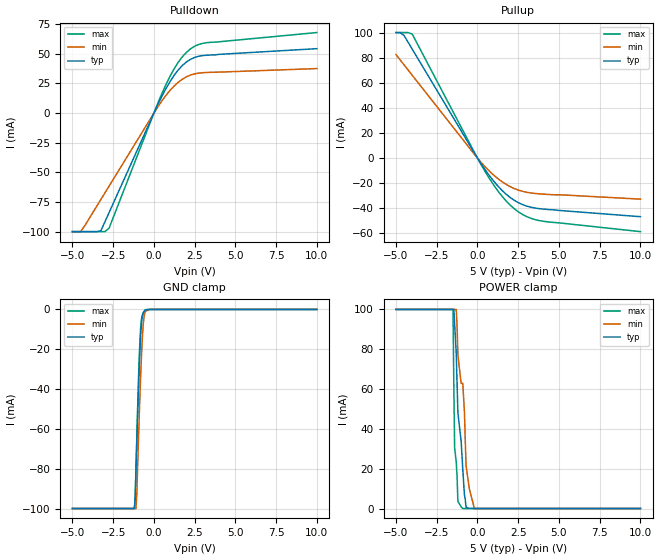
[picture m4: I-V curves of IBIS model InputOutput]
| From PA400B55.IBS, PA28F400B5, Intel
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|********************Input Output Model**************************
[Model]   InputOutput
Model_type   I/O
|   Model for DQ[15:0] pins.
Vinl = 0.8V
Vinh = 2.0V
|Variable   Typ   Min   Max
C_comp   8.91p   NA   10.5p
[Voltage Range]   5.0V   4.5V   5.5V
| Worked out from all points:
|   slope of the pulldown table from 0 to 0.75 V, typ, clamps not added: 35.7 ohm
|   slope of the pullup table from 0 to 0.75 V, typ, clamps not added: 52.4 ohm
|   GND clamp passes 1 mA (typ) near -0.59 V on its own axis
|   POWER clamp passes 1 mA (typ) near -0.70 V on its own axis
[Pulldown]
| [Pullup] and [Pulldown] IV curves include only the current through
| the channels of output driver transistors when outputs are enabled
| with OE# = VIL.  Although the output driver transistors have np and
| pn diodes inherently created by CMOS IC fabrication between the
| drain and bulk of n-channel and p-channel CMOS transistors,
| the current through these junction diodes is not included in
| [Pullup] or [Pulldown].  Instead that drain/bulk diode current is
| included in the [POWER_clamp] or [GND_clamp] sections, which are
| not dependent on the state of OE# or output data value.
|Voltage   I(typ)   I(min)   I(max)
-5V       -100mA     -100mA     -100mA
-4.5V     -100mA     -100mA     -100mA
-3.25V    -99.21mA   -72.83mA   -100mA
-3V       -91.58mA   -67.23mA   -100mA
-2.75V    -83.96mA   -61.63mA   -97.09mA
0V        0A         0A         0A
750mV     20.99mA    15.18mA    24.41mA
1.5V      36.53mA    26.1mA     43.01mA
2.25V     45.41mA    32.15mA    54.26mA
2.75V     47.97mA    33.77mA    57.93mA
3.25V     48.88mA    34.32mA    59.45mA
10V       54.4mA     37.6mA     68mA
[GND_clamp]
| [POWER_clamp] and [GND_clamp] IV curves describe ESD protection
| circuits PLUS some np and pn diodes which exist between the
| drain and bulk of n-channel and p-channel CMOS transistors.
| These drain/bulk diodes are inherent in CMOS IC fabrication,
| and are visible on the node of the I/O pin at all times.
| Even the drain/bulk diodes of output driver [Pullup] and [Powerdown]
| transistors are included in [POWER_clamp] or [GND_clamp], because
| these diodes contribute to I/O pin current even when the
| chip outputs are tristated by OE# = VIH.
| For example, when V forced on the I/O pin is large, we are
| forward biasing the pn diode at the drain/bulk interface in the
| p-channel pullup transistor.  Similarly, when V forced on the
| I/O pin is sufficiently negative with respect to the substrate
| ground, we are forward biasing the np diode at the drain/bulk
| interface in the n-channel pulldown transistor.  The effects
| of these diodes are included in [POWER_clamp] or [GND_clamp].
|Voltage   I(typ)   I(min)   I(max)
-5V       -100mA     -100mA     -100mA
-1.2V     -100mA     -100mA     -100mA
-1.15V    -94.55mA   -100mA     -96.67mA
-1.1V     -80.56mA   -100mA     -80.77mA
-1.05V    -66.88mA   -93.22mA   -65.22mA
-950mV    -41mA      -66.42mA   -36.42mA
-850mV    -19.48mA   -42.04mA   -14.41mA
-800mV    -11.39mA   -30.88mA   -7.73mA
-700mV    -3.273mA   -13.05mA   -2.625mA
-650mV    -1.9mA     -7.193mA   -1.603mA
-550mV    -562uA     -1.692mA   -398uA
10V       0A         0A         0A
[Pullup]
| (Voltages for [Pullup] and [POWER_clamp] are specified with
| negative respect to Vcc.  Reference the IBIS documentation
| for more information regarding Vtable = Vcc - Voutput.
| This method keeps -Vds constant for the values in all three
| columns across a line of the table.
| [Pullup] and [Pulldown] IV curves include only the current through
| the channels of output driver transistors when outputs are enabled
| with OE# = VIL.  Although the output driver transistors have np and
| pn diodes inherently created by CMOS IC fabrication between the
| drain and bulk of n-channel and p-channel CMOS transistors,
| the current through these junction diodes is not included in
| [Pullup] or [Pulldown].  Instead that drain/bulk diode current is
| included in the [POWER_clamp] or [GND_clamp] sections, which are
| not dependent on the state of OE# or output data value.
|Voltage  I(typ)   I(min)   I(max)
-5V       100mA      82.46mA    100mA
-4.75V    100mA      78.34mA    100mA
-4.5V     97.62mA    74.21mA    100mA
-4V       86.77mA    65.96mA    98.73mA
250mV     -5.046mA   -3.838mA   -5.815mA
750mV     -14.3mA    -10.62mA   -16.61mA
1.25V     -22.21mA   -16.32mA   -26.12mA
1.75V     -28.68mA   -20.87mA   -34.03mA
2.25V     -33.58mA   -24.23mA   -40.27mA
3V        -38.16mA   -27.19mA   -46.5mA
3.75V     -40.21mA   -28.43mA   -49.67mA
10V       -46.7mA    -32.7mA    -58.6mA
[POWER_clamp]
| (Voltages for [Pullup] and [POWER_clamp] are specified with
| negative respect to Vcc.  Reference the IBIS documentation
| for more information regarding Vtable = Vcc - Voutput.
| This method keeps -Vds constant for the values in all three
| columns across a line of the table.
| [POWER_clamp] and [GND_clamp] IV curves describe ESD protection
| circuits PLUS some np and pn diodes which exist between the
| drain and bulk of n-channel and p-channel CMOS transistors.
| These drain/bulk diodes are inherent in CMOS IC fabrication,
| and are visible on the node of the I/O pin at all times.
| Even the drain/bulk diodes of output driver [Pullup] and [Powerdown]
| transistors are included in [POWER_clamp] or [GND_clamp], because
| these diodes contribute to I/O pin current even when the
| chip outputs are tristated by OE# = VIH.
| For example, when V forced on the I/O pin is large, we are
| forward biasing the pn diode at the drain/bulk interface in the
| p-channel pullup transistor.  Similarly, when V forced on the
| I/O pin is sufficiently negative with respect to the substrate
| ground, we are forward biasing the np diode at the drain/bulk
| interface in the n-channel pulldown transistor.  The effects
| of these diodes are included in [POWER_clamp] or [GND_clamp].
|Voltage I(typ)   I(min)   I(max)
-5V       100mA      100mA      100mA
-1.5V     100mA      100mA      100mA
-1.45V    100mA      100mA      62.38mA
-1.4V     92.69mA    100mA      30.52mA
-1.3V     77.7mA     100mA      23.25mA
-1.2V     48.13mA    77.11mA    3.611mA
-1V       33.7mA     62.87mA    831.5uA
-900mV    19.73mA    62.87mA    0A
-800mV    6.948mA    48.82mA    0A
-700mV    679.5uA    21.69mA    0A
-200mV    0A         0A         0A
10V       0A         0A         0A
[Ramp]
| The DQ Ramp information is not provided at this time for the
| device but will be available in the future.  The table below
| is for the compatibility with some IBIS parsers.
| Variable   typ   min   max
 dV/dt_r   0V/0ns   0V/0ns   0V/0ns
 dV/dt_f   0V/0ns   0V/0ns   0V/0ns
